VERSION 5.7 ;
  NOWIREEXTENSIONATPIN ON ;
  DIVIDERCHAR "/" ;
  BUSBITCHARS "[]" ;
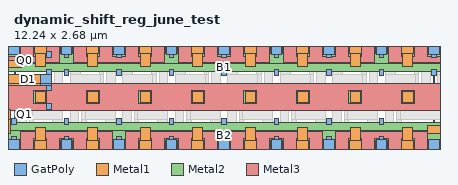
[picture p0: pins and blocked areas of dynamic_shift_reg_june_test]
MACRO dynamic_shift_reg_june_test
  CLASS BLOCK ;
  FOREIGN dynamic_shift_reg_june_test ;
  ORIGIN -8.635 6.860 ;
  SIZE 12.240 BY 2.680 ;
  PIN D0
    ANTENNAGATEAREA 0.093600 ;
    PORT
      LAYER GatPoly ;
        RECT 9.590 -1.580 9.720 -1.400 ;
        RECT 9.590 -2.090 9.720 -1.940 ;
        RECT 9.395 -2.390 9.720 -2.090 ;
        RECT 9.590 -2.560 9.720 -2.390 ;
        RECT 9.590 -3.100 9.720 -2.920 ;
      LAYER Metal1 ;
        RECT 6.385 -2.090 6.790 -2.000 ;
        RECT 6.385 -2.390 9.625 -2.090 ;
        RECT 6.385 -2.475 6.790 -2.390 ;
    END
  END D0
  PIN Q0
    ANTENNADIFFAREA 0.122400 ;
    PORT
      LAYER Metal1 ;
        RECT 6.390 -3.090 6.795 -3.020 ;
        RECT 6.390 -3.390 8.530 -3.090 ;
        RECT 6.390 -3.485 6.795 -3.390 ;
        RECT 8.230 -3.800 8.530 -3.390 ;
    END
  END Q0
  PIN D1
    ANTENNAGATEAREA 0.093600 ;
    PORT
      LAYER GatPoly ;
        RECT 9.590 -4.360 9.720 -4.180 ;
        RECT 9.590 -4.870 9.720 -4.720 ;
        RECT 9.395 -5.170 9.720 -4.870 ;
        RECT 9.590 -5.340 9.720 -5.170 ;
        RECT 9.590 -5.880 9.720 -5.700 ;
      LAYER Metal1 ;
        RECT 6.405 -4.870 6.800 -4.755 ;
        RECT 6.405 -5.170 9.625 -4.870 ;
        RECT 6.405 -5.310 6.800 -5.170 ;
    END
  END D1
  PIN Q1
    ANTENNADIFFAREA 0.122400 ;
    PORT
      LAYER Metal1 ;
        RECT 6.400 -5.870 6.805 -5.760 ;
        RECT 6.400 -6.170 8.530 -5.870 ;
        RECT 6.400 -6.290 6.805 -6.170 ;
        RECT 8.230 -6.580 8.530 -6.170 ;
    END
  END Q1
  PIN VSS
    USE GROUND ;
    PORT
      LAYER Metal1 ;
        RECT 7.875 -1.505 8.175 -1.205 ;
        RECT 9.220 -1.480 9.580 -1.220 ;
        RECT 10.750 -1.480 11.110 -1.220 ;
        RECT 12.280 -1.480 12.640 -1.220 ;
        RECT 13.810 -1.480 14.170 -1.220 ;
        RECT 15.340 -1.480 15.700 -1.220 ;
        RECT 16.870 -1.480 17.230 -1.220 ;
        RECT 18.400 -1.480 18.760 -1.220 ;
        RECT 19.930 -1.480 20.290 -1.220 ;
        RECT 8.010 -1.670 8.175 -1.505 ;
        RECT 8.010 -1.885 8.850 -1.670 ;
        RECT 9.250 -1.840 9.550 -1.480 ;
        RECT 10.780 -1.840 11.080 -1.480 ;
        RECT 12.310 -1.840 12.610 -1.480 ;
        RECT 13.840 -1.840 14.140 -1.480 ;
        RECT 15.370 -1.840 15.670 -1.480 ;
        RECT 16.900 -1.840 17.200 -1.480 ;
        RECT 18.430 -1.840 18.730 -1.480 ;
        RECT 19.960 -1.840 20.260 -1.480 ;
        RECT 21.345 -1.485 21.645 -1.205 ;
        RECT 21.480 -1.670 21.645 -1.485 ;
        RECT 21.480 -1.885 22.320 -1.670 ;
        RECT 7.200 -3.810 8.040 -3.580 ;
        RECT 7.875 -3.990 8.040 -3.810 ;
        RECT 7.875 -4.285 8.175 -3.990 ;
        RECT 9.250 -4.000 9.550 -3.640 ;
        RECT 10.780 -4.000 11.080 -3.640 ;
        RECT 12.310 -4.000 12.610 -3.640 ;
        RECT 13.840 -4.000 14.140 -3.640 ;
        RECT 15.370 -4.000 15.670 -3.640 ;
        RECT 16.900 -4.000 17.200 -3.640 ;
        RECT 18.430 -4.000 18.730 -3.640 ;
        RECT 19.960 -4.000 20.260 -3.640 ;
        RECT 20.670 -3.810 21.510 -3.580 ;
        RECT 21.345 -3.990 21.510 -3.810 ;
        RECT 9.220 -4.260 9.580 -4.000 ;
        RECT 10.750 -4.260 11.110 -4.000 ;
        RECT 12.280 -4.260 12.640 -4.000 ;
        RECT 13.810 -4.260 14.170 -4.000 ;
        RECT 15.340 -4.260 15.700 -4.000 ;
        RECT 16.870 -4.260 17.230 -4.000 ;
        RECT 18.400 -4.260 18.760 -4.000 ;
        RECT 19.930 -4.260 20.290 -4.000 ;
        RECT 8.010 -4.450 8.175 -4.285 ;
        RECT 8.010 -4.665 8.850 -4.450 ;
        RECT 9.250 -4.620 9.550 -4.260 ;
        RECT 10.780 -4.620 11.080 -4.260 ;
        RECT 12.310 -4.620 12.610 -4.260 ;
        RECT 13.840 -4.620 14.140 -4.260 ;
        RECT 15.370 -4.620 15.670 -4.260 ;
        RECT 16.900 -4.620 17.200 -4.260 ;
        RECT 18.430 -4.620 18.730 -4.260 ;
        RECT 19.960 -4.620 20.260 -4.260 ;
        RECT 21.345 -4.280 21.645 -3.990 ;
        RECT 21.480 -4.450 21.645 -4.280 ;
        RECT 21.480 -4.665 22.320 -4.450 ;
        RECT 7.200 -6.590 8.040 -6.360 ;
        RECT 7.875 -6.770 8.040 -6.590 ;
        RECT 7.875 -7.060 8.175 -6.770 ;
        RECT 9.250 -6.780 9.550 -6.420 ;
        RECT 10.780 -6.780 11.080 -6.420 ;
        RECT 12.310 -6.780 12.610 -6.420 ;
        RECT 13.840 -6.780 14.140 -6.420 ;
        RECT 15.370 -6.780 15.670 -6.420 ;
        RECT 16.900 -6.780 17.200 -6.420 ;
        RECT 18.430 -6.780 18.730 -6.420 ;
        RECT 19.960 -6.780 20.260 -6.420 ;
        RECT 20.675 -6.590 21.515 -6.360 ;
        RECT 21.350 -6.770 21.515 -6.590 ;
        RECT 9.220 -7.040 9.580 -6.780 ;
        RECT 10.750 -7.040 11.110 -6.780 ;
        RECT 12.280 -7.040 12.640 -6.780 ;
        RECT 13.810 -7.040 14.170 -6.780 ;
        RECT 15.340 -7.040 15.700 -6.780 ;
        RECT 16.870 -7.040 17.230 -6.780 ;
        RECT 18.400 -7.040 18.760 -6.780 ;
        RECT 19.930 -7.040 20.290 -6.780 ;
        RECT 8.010 -7.225 8.175 -7.060 ;
        RECT 21.350 -7.065 21.650 -6.770 ;
        RECT 8.010 -7.440 8.850 -7.225 ;
        RECT 21.485 -7.230 21.650 -7.065 ;
        RECT 21.485 -7.445 22.325 -7.230 ;
      LAYER Metal2 ;
        RECT 7.830 -1.545 8.220 -1.155 ;
        RECT 9.205 -1.545 9.595 -1.155 ;
        RECT 10.735 -1.545 11.125 -1.155 ;
        RECT 12.265 -1.545 12.655 -1.155 ;
        RECT 13.795 -1.545 14.185 -1.155 ;
        RECT 15.325 -1.545 15.715 -1.155 ;
        RECT 16.855 -1.545 17.245 -1.155 ;
        RECT 18.385 -1.545 18.775 -1.155 ;
        RECT 19.915 -1.545 20.305 -1.155 ;
        RECT 21.300 -1.545 21.690 -1.155 ;
        RECT 7.825 -4.325 8.215 -3.935 ;
        RECT 9.205 -4.325 9.595 -3.935 ;
        RECT 10.735 -4.325 11.125 -3.935 ;
        RECT 12.265 -4.325 12.655 -3.935 ;
        RECT 13.795 -4.325 14.185 -3.935 ;
        RECT 15.325 -4.325 15.715 -3.935 ;
        RECT 16.855 -4.325 17.245 -3.935 ;
        RECT 18.385 -4.325 18.775 -3.935 ;
        RECT 19.915 -4.325 20.305 -3.935 ;
        RECT 21.300 -4.325 21.690 -3.935 ;
        RECT 7.830 -7.105 8.220 -6.715 ;
        RECT 9.205 -7.105 9.595 -6.715 ;
        RECT 10.735 -7.105 11.125 -6.715 ;
        RECT 12.265 -7.105 12.655 -6.715 ;
        RECT 13.795 -7.105 14.185 -6.715 ;
        RECT 15.325 -7.105 15.715 -6.715 ;
        RECT 16.855 -7.105 17.245 -6.715 ;
        RECT 18.385 -7.105 18.775 -6.715 ;
        RECT 19.915 -7.105 20.305 -6.715 ;
        RECT 21.305 -7.100 21.695 -6.710 ;
      LAYER Metal3 ;
        RECT 7.550 -1.745 23.015 -0.955 ;
        RECT 22.590 -3.735 23.015 -1.745 ;
        RECT 7.770 -4.525 23.015 -3.735 ;
        RECT 22.555 -6.515 22.980 -4.525 ;
        RECT 7.505 -7.305 22.980 -6.515 ;
    END
  END VSS
  PIN VDD
    USE POWER ;
    PORT
      LAYER Metal1 ;
        RECT 7.700 -2.890 8.340 -2.590 ;
        RECT 9.255 -2.890 9.555 -2.590 ;
        RECT 10.785 -2.890 11.085 -2.590 ;
        RECT 12.315 -2.890 12.615 -2.590 ;
        RECT 13.845 -2.890 14.145 -2.590 ;
        RECT 15.375 -2.890 15.675 -2.590 ;
        RECT 16.905 -2.890 17.205 -2.590 ;
        RECT 18.435 -2.890 18.735 -2.590 ;
        RECT 19.965 -2.890 20.265 -2.590 ;
        RECT 21.170 -2.890 21.810 -2.590 ;
        RECT 7.700 -5.670 8.340 -5.370 ;
        RECT 9.255 -5.670 9.555 -5.370 ;
        RECT 10.785 -5.670 11.085 -5.370 ;
        RECT 12.315 -5.670 12.615 -5.370 ;
        RECT 13.845 -5.670 14.145 -5.370 ;
        RECT 15.375 -5.670 15.675 -5.370 ;
        RECT 16.905 -5.670 17.205 -5.370 ;
        RECT 18.435 -5.670 18.735 -5.370 ;
        RECT 19.965 -5.670 20.265 -5.370 ;
        RECT 21.170 -5.670 21.810 -5.370 ;
      LAYER Metal2 ;
        RECT 7.675 -2.915 8.365 -2.570 ;
        RECT 9.205 -2.935 9.595 -2.545 ;
        RECT 10.735 -2.935 11.125 -2.545 ;
        RECT 12.265 -2.935 12.655 -2.545 ;
        RECT 13.795 -2.935 14.185 -2.545 ;
        RECT 15.325 -2.935 15.715 -2.545 ;
        RECT 16.855 -2.935 17.245 -2.545 ;
        RECT 18.385 -2.935 18.775 -2.545 ;
        RECT 19.915 -2.935 20.305 -2.545 ;
        RECT 21.145 -2.915 21.835 -2.570 ;
        RECT 7.675 -5.700 8.365 -5.355 ;
        RECT 9.205 -5.715 9.595 -5.325 ;
        RECT 10.735 -5.715 11.125 -5.325 ;
        RECT 12.265 -5.715 12.655 -5.325 ;
        RECT 13.795 -5.715 14.185 -5.325 ;
        RECT 15.325 -5.715 15.715 -5.325 ;
        RECT 16.855 -5.715 17.245 -5.325 ;
        RECT 18.385 -5.715 18.775 -5.325 ;
        RECT 19.915 -5.715 20.305 -5.325 ;
        RECT 21.145 -5.700 21.835 -5.355 ;
      LAYER Metal3 ;
        RECT 7.070 -3.125 22.090 -2.335 ;
        RECT 7.070 -5.115 7.405 -3.125 ;
        RECT 7.070 -5.120 20.875 -5.115 ;
        RECT 7.070 -5.905 22.090 -5.120 ;
        RECT 20.875 -5.910 22.090 -5.905 ;
    END
  END VDD
  PIN B2
    ANTENNAGATEAREA 0.187200 ;
    PORT
      LAYER GatPoly ;
        RECT 10.100 -6.320 10.230 -6.140 ;
        RECT 13.160 -6.320 13.290 -6.140 ;
        RECT 16.220 -6.320 16.350 -6.140 ;
        RECT 19.280 -6.320 19.410 -6.140 ;
        RECT 10.100 -6.760 10.230 -6.680 ;
        RECT 13.160 -6.760 13.290 -6.680 ;
        RECT 16.220 -6.760 16.350 -6.680 ;
        RECT 19.280 -6.760 19.410 -6.680 ;
        RECT 10.015 -7.060 10.315 -6.760 ;
        RECT 13.075 -7.060 13.375 -6.760 ;
        RECT 16.135 -7.060 16.435 -6.760 ;
        RECT 19.195 -7.060 19.495 -6.760 ;
      LAYER Metal1 ;
        RECT 9.985 -7.040 10.345 -6.780 ;
        RECT 13.045 -7.040 13.405 -6.780 ;
        RECT 16.105 -7.040 16.465 -6.780 ;
        RECT 19.165 -7.040 19.525 -6.780 ;
      LAYER Metal2 ;
        RECT 5.895 -7.315 6.255 -7.195 ;
        RECT 9.970 -7.315 10.360 -6.715 ;
        RECT 13.030 -7.315 13.420 -6.715 ;
        RECT 16.090 -7.315 16.480 -6.715 ;
        RECT 19.150 -7.315 19.540 -6.715 ;
        RECT 5.895 -7.555 21.255 -7.315 ;
        RECT 5.895 -7.700 6.255 -7.555 ;
    END
  END B2
  PIN A2
    ANTENNAGATEAREA 0.187200 ;
    PORT
      LAYER GatPoly ;
        RECT 8.570 -6.320 8.700 -6.140 ;
        RECT 11.630 -6.320 11.760 -6.140 ;
        RECT 14.690 -6.320 14.820 -6.140 ;
        RECT 17.750 -6.320 17.880 -6.140 ;
        RECT 8.570 -6.760 8.700 -6.680 ;
        RECT 11.630 -6.760 11.760 -6.680 ;
        RECT 14.690 -6.760 14.820 -6.680 ;
        RECT 17.750 -6.760 17.880 -6.680 ;
        RECT 8.485 -7.060 8.785 -6.760 ;
        RECT 11.545 -7.060 11.845 -6.760 ;
        RECT 14.605 -7.060 14.905 -6.760 ;
        RECT 17.665 -7.060 17.965 -6.760 ;
        RECT 20.725 -7.060 21.025 -6.760 ;
      LAYER Metal1 ;
        RECT 8.455 -7.040 8.815 -6.780 ;
        RECT 11.515 -7.040 11.875 -6.780 ;
        RECT 14.575 -7.040 14.935 -6.780 ;
        RECT 17.635 -7.040 17.995 -6.780 ;
        RECT 20.695 -7.040 21.055 -6.780 ;
      LAYER Metal2 ;
        RECT 5.885 -6.265 6.255 -6.155 ;
        RECT 5.885 -6.505 21.255 -6.265 ;
        RECT 5.885 -6.650 6.255 -6.505 ;
        RECT 8.440 -7.105 8.830 -6.505 ;
        RECT 11.500 -7.105 11.890 -6.505 ;
        RECT 14.560 -7.105 14.950 -6.505 ;
        RECT 17.620 -7.105 18.010 -6.505 ;
        RECT 20.680 -7.105 21.070 -6.505 ;
    END
  END A2
  PIN B1
    ANTENNAGATEAREA 0.374400 ;
    PORT
      LAYER GatPoly ;
        RECT 10.100 -3.540 10.230 -3.360 ;
        RECT 13.160 -3.540 13.290 -3.360 ;
        RECT 16.220 -3.540 16.350 -3.360 ;
        RECT 19.280 -3.540 19.410 -3.360 ;
        RECT 10.100 -3.980 10.230 -3.900 ;
        RECT 13.160 -3.980 13.290 -3.900 ;
        RECT 16.220 -3.980 16.350 -3.900 ;
        RECT 19.280 -3.980 19.410 -3.900 ;
        RECT 10.015 -4.280 10.315 -3.980 ;
        RECT 13.075 -4.280 13.375 -3.980 ;
        RECT 16.135 -4.280 16.435 -3.980 ;
        RECT 19.195 -4.280 19.495 -3.980 ;
        RECT 10.100 -4.360 10.230 -4.280 ;
        RECT 13.160 -4.360 13.290 -4.280 ;
        RECT 16.220 -4.360 16.350 -4.280 ;
        RECT 19.280 -4.360 19.410 -4.280 ;
        RECT 10.100 -4.900 10.230 -4.720 ;
        RECT 13.160 -4.900 13.290 -4.720 ;
        RECT 16.220 -4.900 16.350 -4.720 ;
        RECT 19.280 -4.900 19.410 -4.720 ;
      LAYER Metal1 ;
        RECT 9.985 -4.260 10.345 -4.000 ;
        RECT 13.045 -4.260 13.405 -4.000 ;
        RECT 16.105 -4.260 16.465 -4.000 ;
        RECT 19.165 -4.260 19.525 -4.000 ;
      LAYER Metal2 ;
        RECT 5.875 -4.535 6.235 -4.385 ;
        RECT 9.970 -4.535 10.360 -3.935 ;
        RECT 13.030 -4.535 13.420 -3.935 ;
        RECT 16.090 -4.535 16.480 -3.935 ;
        RECT 19.150 -4.535 19.540 -3.935 ;
        RECT 5.875 -4.775 21.255 -4.535 ;
        RECT 5.875 -4.885 6.235 -4.775 ;
    END
  END B1
  PIN A1
    ANTENNAGATEAREA 0.374400 ;
    PORT
      LAYER GatPoly ;
        RECT 8.570 -3.540 8.700 -3.360 ;
        RECT 11.630 -3.540 11.760 -3.360 ;
        RECT 14.690 -3.540 14.820 -3.360 ;
        RECT 17.750 -3.540 17.880 -3.360 ;
        RECT 8.570 -3.980 8.700 -3.900 ;
        RECT 11.630 -3.980 11.760 -3.900 ;
        RECT 14.690 -3.980 14.820 -3.900 ;
        RECT 17.750 -3.980 17.880 -3.900 ;
        RECT 8.485 -4.280 8.785 -3.980 ;
        RECT 11.545 -4.280 11.845 -3.980 ;
        RECT 14.605 -4.280 14.905 -3.980 ;
        RECT 17.665 -4.280 17.965 -3.980 ;
        RECT 20.725 -4.280 21.025 -3.980 ;
        RECT 11.630 -4.360 11.760 -4.280 ;
        RECT 14.690 -4.360 14.820 -4.280 ;
        RECT 17.750 -4.360 17.880 -4.280 ;
        RECT 20.810 -4.360 20.940 -4.280 ;
        RECT 11.630 -4.900 11.760 -4.720 ;
        RECT 14.690 -4.900 14.820 -4.720 ;
        RECT 17.750 -4.900 17.880 -4.720 ;
        RECT 20.810 -4.900 20.940 -4.720 ;
      LAYER Metal1 ;
        RECT 8.455 -4.260 8.815 -4.000 ;
        RECT 11.515 -4.260 11.875 -4.000 ;
        RECT 14.575 -4.260 14.935 -4.000 ;
        RECT 17.635 -4.260 17.995 -4.000 ;
        RECT 20.695 -4.260 21.055 -4.000 ;
      LAYER Metal2 ;
        RECT 5.870 -3.485 6.240 -3.340 ;
        RECT 5.870 -3.725 21.255 -3.485 ;
        RECT 5.870 -3.855 6.240 -3.725 ;
        RECT 8.440 -4.325 8.830 -3.725 ;
        RECT 11.500 -4.325 11.890 -3.725 ;
        RECT 14.560 -4.325 14.950 -3.725 ;
        RECT 17.620 -4.325 18.010 -3.725 ;
        RECT 20.680 -4.325 21.070 -3.725 ;
    END
  END A1
  PIN B0
    ANTENNAGATEAREA 0.187200 ;
    PORT
      LAYER GatPoly ;
        RECT 10.015 -1.500 10.315 -1.200 ;
        RECT 13.075 -1.500 13.375 -1.200 ;
        RECT 16.135 -1.500 16.435 -1.200 ;
        RECT 19.195 -1.500 19.495 -1.200 ;
        RECT 10.100 -1.580 10.230 -1.500 ;
        RECT 13.160 -1.580 13.290 -1.500 ;
        RECT 16.220 -1.580 16.350 -1.500 ;
        RECT 19.280 -1.580 19.410 -1.500 ;
        RECT 10.100 -2.120 10.230 -1.940 ;
        RECT 13.160 -2.120 13.290 -1.940 ;
        RECT 16.220 -2.120 16.350 -1.940 ;
        RECT 19.280 -2.120 19.410 -1.940 ;
      LAYER Metal1 ;
        RECT 9.985 -1.480 10.345 -1.220 ;
        RECT 13.045 -1.480 13.405 -1.220 ;
        RECT 16.105 -1.480 16.465 -1.220 ;
        RECT 19.165 -1.480 19.525 -1.220 ;
      LAYER Metal2 ;
        RECT 5.860 -1.755 6.245 -1.620 ;
        RECT 9.970 -1.755 10.360 -1.155 ;
        RECT 13.030 -1.755 13.420 -1.155 ;
        RECT 16.090 -1.755 16.480 -1.155 ;
        RECT 19.150 -1.755 19.540 -1.155 ;
        RECT 5.860 -1.995 21.255 -1.755 ;
        RECT 5.860 -2.140 6.245 -1.995 ;
    END
  END B0
  PIN A0
    ANTENNAGATEAREA 0.187200 ;
    PORT
      LAYER GatPoly ;
        RECT 8.485 -1.500 8.785 -1.200 ;
        RECT 11.545 -1.500 11.845 -1.200 ;
        RECT 14.605 -1.500 14.905 -1.200 ;
        RECT 17.665 -1.500 17.965 -1.200 ;
        RECT 20.725 -1.500 21.025 -1.200 ;
        RECT 11.630 -1.580 11.760 -1.500 ;
        RECT 14.690 -1.580 14.820 -1.500 ;
        RECT 17.750 -1.580 17.880 -1.500 ;
        RECT 20.810 -1.580 20.940 -1.500 ;
        RECT 11.630 -2.120 11.760 -1.940 ;
        RECT 14.690 -2.120 14.820 -1.940 ;
        RECT 17.750 -2.120 17.880 -1.940 ;
        RECT 20.810 -2.120 20.940 -1.940 ;
      LAYER Metal1 ;
        RECT 8.455 -1.480 8.815 -1.220 ;
        RECT 11.515 -1.480 11.875 -1.220 ;
        RECT 14.575 -1.480 14.935 -1.220 ;
        RECT 17.635 -1.480 17.995 -1.220 ;
        RECT 20.695 -1.480 21.055 -1.220 ;
      LAYER Metal2 ;
        RECT 5.855 -0.705 6.240 -0.595 ;
        RECT 5.855 -0.945 21.255 -0.705 ;
        RECT 5.855 -1.100 6.240 -0.945 ;
        RECT 8.440 -1.545 8.830 -0.945 ;
        RECT 11.500 -1.545 11.890 -0.945 ;
        RECT 14.560 -1.545 14.950 -0.945 ;
        RECT 17.620 -1.545 18.010 -0.945 ;
        RECT 20.680 -1.545 21.070 -0.945 ;
    END
  END A0
  OBS
      LAYER GatPoly ;
        RECT 11.120 -1.580 11.250 -1.400 ;
        RECT 12.650 -1.580 12.780 -1.400 ;
        RECT 14.180 -1.580 14.310 -1.400 ;
        RECT 15.710 -1.580 15.840 -1.400 ;
        RECT 17.240 -1.580 17.370 -1.400 ;
        RECT 18.770 -1.580 18.900 -1.400 ;
        RECT 20.300 -1.580 20.430 -1.400 ;
        RECT 11.120 -2.090 11.250 -1.940 ;
        RECT 12.650 -2.090 12.780 -1.940 ;
        RECT 14.180 -2.090 14.310 -1.940 ;
        RECT 15.710 -2.090 15.840 -1.940 ;
        RECT 17.240 -2.090 17.370 -1.940 ;
        RECT 18.770 -2.090 18.900 -1.940 ;
        RECT 20.300 -2.090 20.430 -1.940 ;
        RECT 9.080 -2.560 9.210 -2.380 ;
        RECT 10.610 -2.560 10.740 -2.380 ;
        RECT 10.925 -2.390 11.250 -2.090 ;
        RECT 11.120 -2.560 11.250 -2.390 ;
        RECT 12.140 -2.560 12.270 -2.380 ;
        RECT 12.455 -2.390 12.780 -2.090 ;
        RECT 12.650 -2.560 12.780 -2.390 ;
        RECT 13.670 -2.560 13.800 -2.380 ;
        RECT 13.985 -2.390 14.310 -2.090 ;
        RECT 14.180 -2.560 14.310 -2.390 ;
        RECT 15.200 -2.560 15.330 -2.380 ;
        RECT 15.515 -2.390 15.840 -2.090 ;
        RECT 15.710 -2.560 15.840 -2.390 ;
        RECT 16.730 -2.560 16.860 -2.380 ;
        RECT 17.045 -2.390 17.370 -2.090 ;
        RECT 17.240 -2.560 17.370 -2.390 ;
        RECT 18.260 -2.560 18.390 -2.380 ;
        RECT 18.575 -2.390 18.900 -2.090 ;
        RECT 18.770 -2.560 18.900 -2.390 ;
        RECT 19.790 -2.560 19.920 -2.380 ;
        RECT 20.105 -2.390 20.430 -2.090 ;
        RECT 20.300 -2.560 20.430 -2.390 ;
        RECT 9.080 -3.090 9.210 -2.920 ;
        RECT 10.610 -3.090 10.740 -2.920 ;
        RECT 9.080 -3.390 9.405 -3.090 ;
        RECT 10.610 -3.390 10.935 -3.090 ;
        RECT 11.120 -3.100 11.250 -2.920 ;
        RECT 12.140 -3.090 12.270 -2.920 ;
        RECT 12.140 -3.390 12.465 -3.090 ;
        RECT 12.650 -3.100 12.780 -2.920 ;
        RECT 13.670 -3.090 13.800 -2.920 ;
        RECT 13.670 -3.390 13.995 -3.090 ;
        RECT 14.180 -3.100 14.310 -2.920 ;
        RECT 15.200 -3.090 15.330 -2.920 ;
        RECT 15.200 -3.390 15.525 -3.090 ;
        RECT 15.710 -3.100 15.840 -2.920 ;
        RECT 16.730 -3.090 16.860 -2.920 ;
        RECT 16.730 -3.390 17.055 -3.090 ;
        RECT 17.240 -3.100 17.370 -2.920 ;
        RECT 18.260 -3.090 18.390 -2.920 ;
        RECT 18.260 -3.390 18.585 -3.090 ;
        RECT 18.770 -3.100 18.900 -2.920 ;
        RECT 19.790 -3.090 19.920 -2.920 ;
        RECT 19.790 -3.390 20.115 -3.090 ;
        RECT 20.300 -3.100 20.430 -2.920 ;
        RECT 9.080 -3.540 9.210 -3.390 ;
        RECT 10.610 -3.540 10.740 -3.390 ;
        RECT 12.140 -3.540 12.270 -3.390 ;
        RECT 13.670 -3.540 13.800 -3.390 ;
        RECT 15.200 -3.540 15.330 -3.390 ;
        RECT 16.730 -3.540 16.860 -3.390 ;
        RECT 18.260 -3.540 18.390 -3.390 ;
        RECT 19.790 -3.540 19.920 -3.390 ;
        RECT 9.080 -4.080 9.210 -3.900 ;
        RECT 10.610 -4.080 10.740 -3.900 ;
        RECT 12.140 -4.080 12.270 -3.900 ;
        RECT 13.670 -4.080 13.800 -3.900 ;
        RECT 15.200 -4.080 15.330 -3.900 ;
        RECT 16.730 -4.080 16.860 -3.900 ;
        RECT 18.260 -4.080 18.390 -3.900 ;
        RECT 19.790 -4.080 19.920 -3.900 ;
        RECT 11.120 -4.360 11.250 -4.180 ;
        RECT 12.650 -4.360 12.780 -4.180 ;
        RECT 14.180 -4.360 14.310 -4.180 ;
        RECT 15.710 -4.360 15.840 -4.180 ;
        RECT 17.240 -4.360 17.370 -4.180 ;
        RECT 18.770 -4.360 18.900 -4.180 ;
        RECT 20.300 -4.360 20.430 -4.180 ;
        RECT 11.120 -4.870 11.250 -4.720 ;
        RECT 12.650 -4.870 12.780 -4.720 ;
        RECT 14.180 -4.870 14.310 -4.720 ;
        RECT 15.710 -4.870 15.840 -4.720 ;
        RECT 17.240 -4.870 17.370 -4.720 ;
        RECT 18.770 -4.870 18.900 -4.720 ;
        RECT 20.300 -4.870 20.430 -4.720 ;
        RECT 9.080 -5.340 9.210 -5.160 ;
        RECT 10.610 -5.340 10.740 -5.160 ;
        RECT 10.925 -5.170 11.250 -4.870 ;
        RECT 11.120 -5.340 11.250 -5.170 ;
        RECT 12.140 -5.340 12.270 -5.160 ;
        RECT 12.455 -5.170 12.780 -4.870 ;
        RECT 12.650 -5.340 12.780 -5.170 ;
        RECT 13.670 -5.340 13.800 -5.160 ;
        RECT 13.985 -5.170 14.310 -4.870 ;
        RECT 14.180 -5.340 14.310 -5.170 ;
        RECT 15.200 -5.340 15.330 -5.160 ;
        RECT 15.515 -5.170 15.840 -4.870 ;
        RECT 15.710 -5.340 15.840 -5.170 ;
        RECT 16.730 -5.340 16.860 -5.160 ;
        RECT 17.045 -5.170 17.370 -4.870 ;
        RECT 17.240 -5.340 17.370 -5.170 ;
        RECT 18.260 -5.340 18.390 -5.160 ;
        RECT 18.575 -5.170 18.900 -4.870 ;
        RECT 18.770 -5.340 18.900 -5.170 ;
        RECT 19.790 -5.340 19.920 -5.160 ;
        RECT 20.105 -5.170 20.430 -4.870 ;
        RECT 20.300 -5.340 20.430 -5.170 ;
        RECT 9.080 -5.870 9.210 -5.700 ;
        RECT 10.610 -5.870 10.740 -5.700 ;
        RECT 9.080 -6.170 9.405 -5.870 ;
        RECT 10.610 -6.170 10.935 -5.870 ;
        RECT 11.120 -5.880 11.250 -5.700 ;
        RECT 12.140 -5.870 12.270 -5.700 ;
        RECT 12.140 -6.170 12.465 -5.870 ;
        RECT 12.650 -5.880 12.780 -5.700 ;
        RECT 13.670 -5.870 13.800 -5.700 ;
        RECT 13.670 -6.170 13.995 -5.870 ;
        RECT 14.180 -5.880 14.310 -5.700 ;
        RECT 15.200 -5.870 15.330 -5.700 ;
        RECT 15.200 -6.170 15.525 -5.870 ;
        RECT 15.710 -5.880 15.840 -5.700 ;
        RECT 16.730 -5.870 16.860 -5.700 ;
        RECT 16.730 -6.170 17.055 -5.870 ;
        RECT 17.240 -5.880 17.370 -5.700 ;
        RECT 18.260 -5.870 18.390 -5.700 ;
        RECT 18.260 -6.170 18.585 -5.870 ;
        RECT 18.770 -5.880 18.900 -5.700 ;
        RECT 19.790 -5.870 19.920 -5.700 ;
        RECT 19.790 -6.170 20.115 -5.870 ;
        RECT 20.300 -5.880 20.430 -5.700 ;
        RECT 9.080 -6.320 9.210 -6.170 ;
        RECT 10.610 -6.320 10.740 -6.170 ;
        RECT 12.140 -6.320 12.270 -6.170 ;
        RECT 13.670 -6.320 13.800 -6.170 ;
        RECT 15.200 -6.320 15.330 -6.170 ;
        RECT 16.730 -6.320 16.860 -6.170 ;
        RECT 18.260 -6.320 18.390 -6.170 ;
        RECT 19.790 -6.320 19.920 -6.170 ;
        RECT 9.080 -6.860 9.210 -6.680 ;
        RECT 10.610 -6.860 10.740 -6.680 ;
        RECT 12.140 -6.860 12.270 -6.680 ;
        RECT 13.670 -6.860 13.800 -6.680 ;
        RECT 15.200 -6.860 15.330 -6.680 ;
        RECT 16.730 -6.860 16.860 -6.680 ;
        RECT 18.260 -6.860 18.390 -6.680 ;
        RECT 19.790 -6.860 19.920 -6.680 ;
      LAYER Metal1 ;
        RECT 9.760 -1.910 10.060 -1.680 ;
        RECT 9.805 -2.570 10.060 -1.910 ;
        RECT 10.270 -2.090 10.570 -1.680 ;
        RECT 11.290 -1.910 11.590 -1.680 ;
        RECT 10.270 -2.390 11.155 -2.090 ;
        RECT 11.335 -2.570 11.590 -1.910 ;
        RECT 11.800 -2.090 12.100 -1.680 ;
        RECT 12.820 -1.910 13.120 -1.680 ;
        RECT 11.800 -2.390 12.685 -2.090 ;
        RECT 12.865 -2.570 13.120 -1.910 ;
        RECT 13.330 -2.090 13.630 -1.680 ;
        RECT 14.350 -1.910 14.650 -1.680 ;
        RECT 13.330 -2.390 14.215 -2.090 ;
        RECT 14.395 -2.570 14.650 -1.910 ;
        RECT 14.860 -2.090 15.160 -1.680 ;
        RECT 15.880 -1.910 16.180 -1.680 ;
        RECT 14.860 -2.390 15.745 -2.090 ;
        RECT 15.925 -2.570 16.180 -1.910 ;
        RECT 16.390 -2.090 16.690 -1.680 ;
        RECT 17.410 -1.910 17.710 -1.680 ;
        RECT 16.390 -2.390 17.275 -2.090 ;
        RECT 17.455 -2.570 17.710 -1.910 ;
        RECT 17.920 -2.090 18.220 -1.680 ;
        RECT 18.940 -1.910 19.240 -1.680 ;
        RECT 17.920 -2.390 18.805 -2.090 ;
        RECT 18.985 -2.570 19.240 -1.910 ;
        RECT 19.450 -2.090 19.750 -1.680 ;
        RECT 20.470 -1.910 20.770 -1.680 ;
        RECT 19.450 -2.390 20.335 -2.090 ;
        RECT 20.515 -2.570 20.770 -1.910 ;
        RECT 20.980 -2.090 21.280 -1.680 ;
        RECT 20.980 -2.390 22.405 -2.090 ;
        RECT 8.740 -2.910 9.040 -2.590 ;
        RECT 9.760 -2.890 10.060 -2.570 ;
        RECT 10.270 -2.910 10.570 -2.590 ;
        RECT 11.290 -2.890 11.590 -2.570 ;
        RECT 11.800 -2.910 12.100 -2.590 ;
        RECT 12.820 -2.890 13.120 -2.570 ;
        RECT 13.330 -2.910 13.630 -2.590 ;
        RECT 14.350 -2.890 14.650 -2.570 ;
        RECT 14.860 -2.910 15.160 -2.590 ;
        RECT 15.880 -2.890 16.180 -2.570 ;
        RECT 16.390 -2.910 16.690 -2.590 ;
        RECT 17.410 -2.890 17.710 -2.570 ;
        RECT 17.920 -2.910 18.220 -2.590 ;
        RECT 18.940 -2.890 19.240 -2.570 ;
        RECT 19.450 -2.910 19.750 -2.590 ;
        RECT 20.470 -2.890 20.770 -2.570 ;
        RECT 8.740 -3.570 8.995 -2.910 ;
        RECT 9.175 -3.390 10.060 -3.090 ;
        RECT 8.740 -3.800 9.040 -3.570 ;
        RECT 9.760 -3.800 10.060 -3.390 ;
        RECT 10.270 -3.570 10.525 -2.910 ;
        RECT 10.705 -3.390 11.590 -3.090 ;
        RECT 10.270 -3.800 10.570 -3.570 ;
        RECT 11.290 -3.800 11.590 -3.390 ;
        RECT 11.800 -3.570 12.055 -2.910 ;
        RECT 12.235 -3.390 13.120 -3.090 ;
        RECT 11.800 -3.800 12.100 -3.570 ;
        RECT 12.820 -3.800 13.120 -3.390 ;
        RECT 13.330 -3.570 13.585 -2.910 ;
        RECT 13.765 -3.390 14.650 -3.090 ;
        RECT 13.330 -3.800 13.630 -3.570 ;
        RECT 14.350 -3.800 14.650 -3.390 ;
        RECT 14.860 -3.570 15.115 -2.910 ;
        RECT 15.295 -3.390 16.180 -3.090 ;
        RECT 14.860 -3.800 15.160 -3.570 ;
        RECT 15.880 -3.800 16.180 -3.390 ;
        RECT 16.390 -3.570 16.645 -2.910 ;
        RECT 16.825 -3.390 17.710 -3.090 ;
        RECT 16.390 -3.800 16.690 -3.570 ;
        RECT 17.410 -3.800 17.710 -3.390 ;
        RECT 17.920 -3.570 18.175 -2.910 ;
        RECT 18.355 -3.390 19.240 -3.090 ;
        RECT 17.920 -3.800 18.220 -3.570 ;
        RECT 18.940 -3.800 19.240 -3.390 ;
        RECT 19.450 -3.570 19.705 -2.910 ;
        RECT 22.110 -3.090 22.405 -2.390 ;
        RECT 19.885 -3.390 22.405 -3.090 ;
        RECT 19.450 -3.800 19.750 -3.570 ;
        RECT 9.760 -4.690 10.060 -4.460 ;
        RECT 9.805 -5.350 10.060 -4.690 ;
        RECT 10.270 -4.870 10.570 -4.460 ;
        RECT 11.290 -4.690 11.590 -4.460 ;
        RECT 10.270 -5.170 11.155 -4.870 ;
        RECT 11.335 -5.350 11.590 -4.690 ;
        RECT 11.800 -4.870 12.100 -4.460 ;
        RECT 12.820 -4.690 13.120 -4.460 ;
        RECT 11.800 -5.170 12.685 -4.870 ;
        RECT 12.865 -5.350 13.120 -4.690 ;
        RECT 13.330 -4.870 13.630 -4.460 ;
        RECT 14.350 -4.690 14.650 -4.460 ;
        RECT 13.330 -5.170 14.215 -4.870 ;
        RECT 14.395 -5.350 14.650 -4.690 ;
        RECT 14.860 -4.870 15.160 -4.460 ;
        RECT 15.880 -4.690 16.180 -4.460 ;
        RECT 14.860 -5.170 15.745 -4.870 ;
        RECT 15.925 -5.350 16.180 -4.690 ;
        RECT 16.390 -4.870 16.690 -4.460 ;
        RECT 17.410 -4.690 17.710 -4.460 ;
        RECT 16.390 -5.170 17.275 -4.870 ;
        RECT 17.455 -5.350 17.710 -4.690 ;
        RECT 17.920 -4.870 18.220 -4.460 ;
        RECT 18.940 -4.690 19.240 -4.460 ;
        RECT 17.920 -5.170 18.805 -4.870 ;
        RECT 18.985 -5.350 19.240 -4.690 ;
        RECT 19.450 -4.870 19.750 -4.460 ;
        RECT 20.470 -4.690 20.770 -4.460 ;
        RECT 19.450 -5.170 20.335 -4.870 ;
        RECT 20.515 -5.350 20.770 -4.690 ;
        RECT 20.980 -4.870 21.280 -4.460 ;
        RECT 20.980 -5.170 22.405 -4.870 ;
        RECT 8.740 -5.690 9.040 -5.370 ;
        RECT 9.760 -5.670 10.060 -5.350 ;
        RECT 10.270 -5.690 10.570 -5.370 ;
        RECT 11.290 -5.670 11.590 -5.350 ;
        RECT 11.800 -5.690 12.100 -5.370 ;
        RECT 12.820 -5.670 13.120 -5.350 ;
        RECT 13.330 -5.690 13.630 -5.370 ;
        RECT 14.350 -5.670 14.650 -5.350 ;
        RECT 14.860 -5.690 15.160 -5.370 ;
        RECT 15.880 -5.670 16.180 -5.350 ;
        RECT 16.390 -5.690 16.690 -5.370 ;
        RECT 17.410 -5.670 17.710 -5.350 ;
        RECT 17.920 -5.690 18.220 -5.370 ;
        RECT 18.940 -5.670 19.240 -5.350 ;
        RECT 19.450 -5.690 19.750 -5.370 ;
        RECT 20.470 -5.670 20.770 -5.350 ;
        RECT 8.740 -6.350 8.995 -5.690 ;
        RECT 9.175 -6.170 10.060 -5.870 ;
        RECT 8.740 -6.580 9.040 -6.350 ;
        RECT 9.760 -6.580 10.060 -6.170 ;
        RECT 10.270 -6.350 10.525 -5.690 ;
        RECT 10.705 -6.170 11.590 -5.870 ;
        RECT 10.270 -6.580 10.570 -6.350 ;
        RECT 11.290 -6.580 11.590 -6.170 ;
        RECT 11.800 -6.350 12.055 -5.690 ;
        RECT 12.235 -6.170 13.120 -5.870 ;
        RECT 11.800 -6.580 12.100 -6.350 ;
        RECT 12.820 -6.580 13.120 -6.170 ;
        RECT 13.330 -6.350 13.585 -5.690 ;
        RECT 13.765 -6.170 14.650 -5.870 ;
        RECT 13.330 -6.580 13.630 -6.350 ;
        RECT 14.350 -6.580 14.650 -6.170 ;
        RECT 14.860 -6.350 15.115 -5.690 ;
        RECT 15.295 -6.170 16.180 -5.870 ;
        RECT 14.860 -6.580 15.160 -6.350 ;
        RECT 15.880 -6.580 16.180 -6.170 ;
        RECT 16.390 -6.350 16.645 -5.690 ;
        RECT 16.825 -6.170 17.710 -5.870 ;
        RECT 16.390 -6.580 16.690 -6.350 ;
        RECT 17.410 -6.580 17.710 -6.170 ;
        RECT 17.920 -6.350 18.175 -5.690 ;
        RECT 18.355 -6.170 19.240 -5.870 ;
        RECT 17.920 -6.580 18.220 -6.350 ;
        RECT 18.940 -6.580 19.240 -6.170 ;
        RECT 19.450 -6.350 19.705 -5.690 ;
        RECT 22.110 -5.870 22.405 -5.170 ;
        RECT 19.885 -6.170 22.405 -5.870 ;
        RECT 19.450 -6.580 19.750 -6.350 ;
  END
END dynamic_shift_reg_june_test
END LIBRARY

